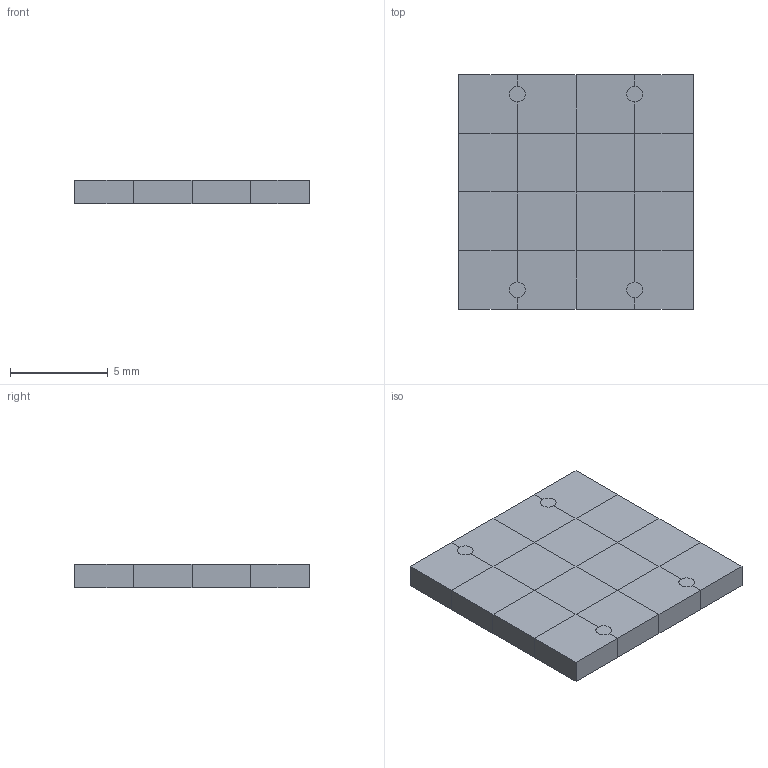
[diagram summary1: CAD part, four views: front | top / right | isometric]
STEP (ISO 10303-21) file: header records copied from the file, then geometry measured from it (millimetres).
FILE_DESCRIPTION(('Open CASCADE Model'),'2;1');
FILE_NAME('Open CASCADE Shape Model','2026-11-27T04:11:50',('Author'),( 'Open CASCADE'),'Open CASCADE STEP processor 7.9','Open CASCADE 7.9' ,'Unknown');
FILE_SCHEMA(('AUTOMOTIVE_DESIGN { 1 0 10303 214 1 1 1 1 }'));
Length unit declared in the file: millimetre
Products named in the file (3): manifold_ML1; fluid; solid
Assembly tree (2 placements, depth 2):
  manifold_ML1
    fluid
    solid
Bounding box: 12 x 12 x 1.2 mm (x, y, z)
Volume: 172.8 mm3; surface area: 1480.4 mm2
Topology: 2 solids, 2 shells, 1992 faces, 6936 edges, 3986 vertices
Faces by surface type: plane 1984, cylinder 8
Full cylindrical faces by diameter (mm): 0.8 x8
Entity records: 162862 total; most frequent: CARTESIAN_POINT 26837, DIRECTION 24814, LINE 20760, VECTOR 20760, ORIENTED_EDGE 13872, PCURVE 13872, DEFINITIONAL_REPRESENTATION 13872, EDGE_CURVE 6936
One B-rep face of a CAD part: STEP entity #87486.
In plain terms, the planar face has unit normal (0, 0, 1).
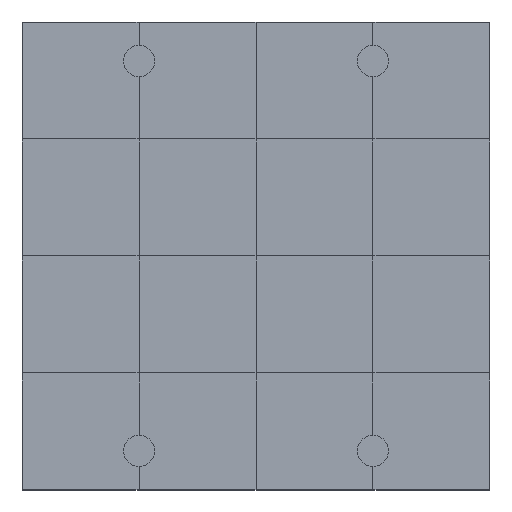
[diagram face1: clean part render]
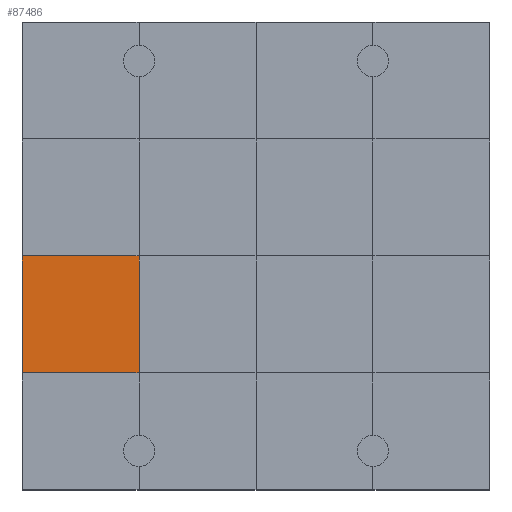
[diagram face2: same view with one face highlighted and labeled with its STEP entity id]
Its self-contained STEP definition (entity closure, numbers rounded to 3 decimals):
#87036 = VERTEX_POINT('',#87037);
#87037 = CARTESIAN_POINT('',(0.,3.,1.2));
#87051 = PLANE('',#87052);
#87052 = AXIS2_PLACEMENT_3D('',#87053,#87054,#87055);
#87053 = CARTESIAN_POINT('',(0.,3.,0.));
#87054 = DIRECTION('',(1.,0.,-0.));
#87055 = DIRECTION('',(0.,0.,1.));
#87077 = PLANE('',#87078);
#87078 = AXIS2_PLACEMENT_3D('',#87079,#87080,#87081);
#87079 = CARTESIAN_POINT('',(0.,0.,1.2));
#87080 = DIRECTION('',(0.,0.,1.));
#87081 = DIRECTION('',(1.,0.,-0.));
#87228 = VERTEX_POINT('',#87229);
#87229 = CARTESIAN_POINT('',(3.,3.,1.2));
#87250 = EDGE_CURVE('',#87036,#87228,#87251,.T.);
#87251 = SURFACE_CURVE('',#87252,(#87256,#87263),.PCURVE_S1.);
#87252 = LINE('',#87253,#87254);
#87253 = CARTESIAN_POINT('',(0.,3.,1.2));
#87254 = VECTOR('',#87255,1.);
#87255 = DIRECTION('',(1.,0.,-0.));
#87256 = PCURVE('',#87077,#87257);
#87257 = DEFINITIONAL_REPRESENTATION('',(#87258),#87262);
#87258 = LINE('',#87259,#87260);
#87259 = CARTESIAN_POINT('',(0.,3.));
#87260 = VECTOR('',#87261,1.);
#87261 = DIRECTION('',(1.,0.));
#87262 = ( GEOMETRIC_REPRESENTATION_CONTEXT(2) 
PARAMETRIC_REPRESENTATION_CONTEXT() REPRESENTATION_CONTEXT('2D SPACE',''
  ) );
#87263 = PCURVE('',#87264,#87269);
#87264 = PLANE('',#87265);
#87265 = AXIS2_PLACEMENT_3D('',#87266,#87267,#87268);
#87266 = CARTESIAN_POINT('',(0.,3.,1.2));
#87267 = DIRECTION('',(0.,0.,1.));
#87268 = DIRECTION('',(1.,0.,-0.));
#87269 = DEFINITIONAL_REPRESENTATION('',(#87270),#87274);
#87270 = LINE('',#87271,#87272);
#87271 = CARTESIAN_POINT('',(0.,0.));
#87272 = VECTOR('',#87273,1.);
#87273 = DIRECTION('',(1.,0.));
#87274 = ( GEOMETRIC_REPRESENTATION_CONTEXT(2) 
PARAMETRIC_REPRESENTATION_CONTEXT() REPRESENTATION_CONTEXT('2D SPACE',''
  ) );
#87309 = VERTEX_POINT('',#87310);
#87310 = CARTESIAN_POINT('',(0.,6.,1.2));
#87336 = EDGE_CURVE('',#87036,#87309,#87337,.T.);
#87337 = SURFACE_CURVE('',#87338,(#87342,#87349),.PCURVE_S1.);
#87338 = LINE('',#87339,#87340);
#87339 = CARTESIAN_POINT('',(0.,3.,1.2));
#87340 = VECTOR('',#87341,1.);
#87341 = DIRECTION('',(-0.,1.,0.));
#87342 = PCURVE('',#87051,#87343);
#87343 = DEFINITIONAL_REPRESENTATION('',(#87344),#87348);
#87344 = LINE('',#87345,#87346);
#87345 = CARTESIAN_POINT('',(1.2,0.));
#87346 = VECTOR('',#87347,1.);
#87347 = DIRECTION('',(0.,-1.));
#87348 = ( GEOMETRIC_REPRESENTATION_CONTEXT(2) 
PARAMETRIC_REPRESENTATION_CONTEXT() REPRESENTATION_CONTEXT('2D SPACE',''
  ) );
#87349 = PCURVE('',#87264,#87350);
#87350 = DEFINITIONAL_REPRESENTATION('',(#87351),#87355);
#87351 = LINE('',#87352,#87353);
#87352 = CARTESIAN_POINT('',(0.,0.));
#87353 = VECTOR('',#87354,1.);
#87354 = DIRECTION('',(0.,1.));
#87355 = ( GEOMETRIC_REPRESENTATION_CONTEXT(2) 
PARAMETRIC_REPRESENTATION_CONTEXT() REPRESENTATION_CONTEXT('2D SPACE',''
  ) );
#87486 = ADVANCED_FACE('',(#87487),#87264,.T.);
#87487 = FACE_BOUND('',#87488,.T.);
#87488 = EDGE_LOOP('',(#87489,#87490,#87491,#87519));
#87489 = ORIENTED_EDGE('',*,*,#87336,.F.);
#87490 = ORIENTED_EDGE('',*,*,#87250,.T.);
#87491 = ORIENTED_EDGE('',*,*,#87492,.T.);
#87492 = EDGE_CURVE('',#87228,#87493,#87495,.T.);
#87493 = VERTEX_POINT('',#87494);
#87494 = CARTESIAN_POINT('',(3.,6.,1.2));
#87495 = SURFACE_CURVE('',#87496,(#87500,#87507),.PCURVE_S1.);
#87496 = LINE('',#87497,#87498);
#87497 = CARTESIAN_POINT('',(3.,3.,1.2));
#87498 = VECTOR('',#87499,1.);
#87499 = DIRECTION('',(-0.,1.,0.));
#87500 = PCURVE('',#87264,#87501);
#87501 = DEFINITIONAL_REPRESENTATION('',(#87502),#87506);
#87502 = LINE('',#87503,#87504);
#87503 = CARTESIAN_POINT('',(3.,0.));
#87504 = VECTOR('',#87505,1.);
#87505 = DIRECTION('',(0.,1.));
#87506 = ( GEOMETRIC_REPRESENTATION_CONTEXT(2) 
PARAMETRIC_REPRESENTATION_CONTEXT() REPRESENTATION_CONTEXT('2D SPACE',''
  ) );
#87507 = PCURVE('',#87508,#87513);
#87508 = PLANE('',#87509);
#87509 = AXIS2_PLACEMENT_3D('',#87510,#87511,#87512);
#87510 = CARTESIAN_POINT('',(3.,3.,1.2));
#87511 = DIRECTION('',(0.,0.,1.));
#87512 = DIRECTION('',(1.,0.,-0.));
#87513 = DEFINITIONAL_REPRESENTATION('',(#87514),#87518);
#87514 = LINE('',#87515,#87516);
#87515 = CARTESIAN_POINT('',(0.,0.));
#87516 = VECTOR('',#87517,1.);
#87517 = DIRECTION('',(0.,1.));
#87518 = ( GEOMETRIC_REPRESENTATION_CONTEXT(2) 
PARAMETRIC_REPRESENTATION_CONTEXT() REPRESENTATION_CONTEXT('2D SPACE',''
  ) );
#87519 = ORIENTED_EDGE('',*,*,#87520,.F.);
#87520 = EDGE_CURVE('',#87309,#87493,#87521,.T.);
#87521 = SURFACE_CURVE('',#87522,(#87526,#87533),.PCURVE_S1.);
#87522 = LINE('',#87523,#87524);
#87523 = CARTESIAN_POINT('',(0.,6.,1.2));
#87524 = VECTOR('',#87525,1.);
#87525 = DIRECTION('',(1.,0.,-0.));
#87526 = PCURVE('',#87264,#87527);
#87527 = DEFINITIONAL_REPRESENTATION('',(#87528),#87532);
#87528 = LINE('',#87529,#87530);
#87529 = CARTESIAN_POINT('',(0.,3.));
#87530 = VECTOR('',#87531,1.);
#87531 = DIRECTION('',(1.,0.));
#87532 = ( GEOMETRIC_REPRESENTATION_CONTEXT(2) 
PARAMETRIC_REPRESENTATION_CONTEXT() REPRESENTATION_CONTEXT('2D SPACE',''
  ) );
#87533 = PCURVE('',#87534,#87539);
#87534 = PLANE('',#87535);
#87535 = AXIS2_PLACEMENT_3D('',#87536,#87537,#87538);
#87536 = CARTESIAN_POINT('',(0.,6.,1.2));
#87537 = DIRECTION('',(0.,0.,1.));
#87538 = DIRECTION('',(1.,0.,-0.));
#87539 = DEFINITIONAL_REPRESENTATION('',(#87540),#87544);
#87540 = LINE('',#87541,#87542);
#87541 = CARTESIAN_POINT('',(0.,0.));
#87542 = VECTOR('',#87543,1.);
#87543 = DIRECTION('',(1.,0.));
#87544 = ( GEOMETRIC_REPRESENTATION_CONTEXT(2) 
PARAMETRIC_REPRESENTATION_CONTEXT() REPRESENTATION_CONTEXT('2D SPACE',''
  ) );
